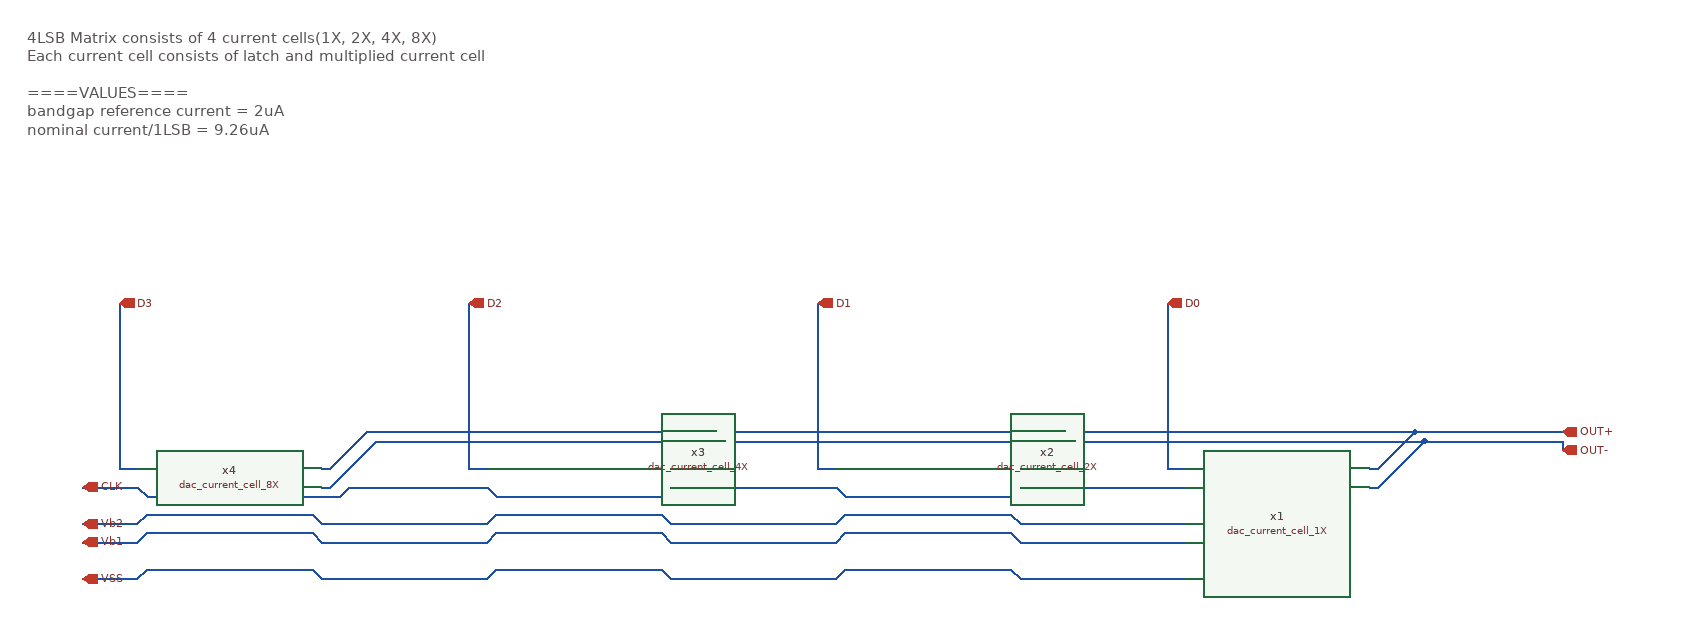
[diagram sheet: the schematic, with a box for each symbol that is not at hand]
v {xschem version=3.4.5 file_version=1.2
}
G {}
K {}
V {}
S {}
E {}
T {4LSB Matrix consists of 4 current cells(1X, 2X, 4X, 8X)
Each current cell consists of latch and multiplied current cell
 
====VALUES====
bandgap reference current = 2uA
nominal current/1LSB = 9.26uA} 20 -890 0 0 0.5 0.5 {}
N 900 -350 910 -360 {
lab=Vb2}
N 720 -290 890 -290 {
lab=VSS}
N 890 -290 900 -290 {
lab=VSS}
N 140 -290 150 -300 {
lab=VSS}
N 150 -300 320 -300 {
lab=VSS}
N 320 -300 330 -300 {
lab=VSS}
N 330 -300 340 -290 {
lab=VSS}
N 340 -290 520 -290 {
lab=VSS}
N 520 -290 530 -300 {
lab=VSS}
N 530 -300 710 -300 {
lab=VSS}
N 710 -300 720 -290 {
lab=VSS}
N 140 -350 150 -360 {
lab=Vb2}
N 150 -360 330 -360 {
lab=Vb2}
N 330 -360 340 -350 {
lab=Vb2}
N 340 -350 520 -350 {
lab=Vb2}
N 140 -330 150 -340 {
lab=Vb1}
N 150 -340 330 -340 {
lab=Vb1}
N 330 -340 340 -330 {
lab=Vb1}
N 340 -330 520 -330 {
lab=Vb1}
N 520 -350 530 -360 {
lab=Vb2}
N 530 -360 710 -360 {
lab=Vb2}
N 710 -360 720 -350 {
lab=Vb2}
N 720 -350 900 -350 {
lab=Vb2}
N 520 -330 530 -340 {
lab=Vb1}
N 530 -340 710 -340 {
lab=Vb1}
N 710 -340 720 -330 {
lab=Vb1}
N 720 -330 900 -330 {
lab=Vb1}
N 510 -390 520 -390 {
lab=CLK}
N 510 -410 520 -410 {
lab=D2}
N 910 -360 1090 -360 {
lab=Vb2}
N 1090 -360 1100 -350 {
lab=Vb2}
N 1100 -350 1280 -350 {
lab=Vb2}
N 900 -330 910 -340 {
lab=Vb1}
N 910 -340 1090 -340 {
lab=Vb1}
N 1090 -340 1100 -330 {
lab=Vb1}
N 1100 -330 1280 -330 {
lab=Vb1}
N 890 -410 900 -410 {
lab=D1}
N 1270 -410 1280 -410 {
lab=D0}
N 500 -590 500 -420 {
lab=D2}
N 500 -410 510 -410 {
lab=D2}
N 500 -420 500 -410 {
lab=D2}
N 120 -410 140 -410 {
lab=D3}
N 120 -590 120 -410 {
lab=D3}
N 880 -410 890 -410 {
lab=D1}
N 880 -590 880 -410 {
lab=D1}
N 1260 -410 1270 -410 {
lab=D0}
N 1260 -590 1260 -410 {
lab=D0}
N 890 -390 900 -390 {
lab=CLK}
N 1270 -390 1280 -390 {
lab=CLK}
N 700 -450 760 -450 {
lab=OUT+}
N 700 -440 770 -440 {
lab=OUT-}
N 760 -450 1140 -450 {
lab=OUT+}
N 770 -440 1150 -440 {
lab=OUT-}
N 1140 -450 1520 -450 {
lab=OUT+}
N 1150 -440 1530 -440 {
lab=OUT-}
N 900 -290 910 -300 {
lab=VSS}
N 910 -300 1090 -300 {
lab=VSS}
N 1090 -300 1100 -290 {
lab=VSS}
N 1100 -290 1280 -290 {
lab=VSS}
N 370 -390 510 -390 {
lab=CLK}
N 340 -390 350 -390 {
lab=OUT-}
N 340 -410 350 -410 {
lab=OUT+}
N 350 -410 390 -450 {
lab=OUT+}
N 720 -410 730 -410 {
lab=OUT+}
N 730 -410 770 -450 {
lab=OUT+}
N 720 -390 730 -390 {
lab=OUT-}
N 740 -390 890 -390 {
lab=CLK}
N 1100 -410 1110 -410 {
lab=OUT+}
N 1110 -410 1150 -450 {
lab=OUT+}
N 1100 -390 1110 -390 {
lab=OUT-}
N 1110 -390 1160 -440 {
lab=OUT-}
N 1120 -390 1270 -390 {
lab=CLK}
N 1480 -410 1490 -410 {
lab=OUT+}
N 1490 -410 1530 -450 {
lab=OUT+}
N 1480 -390 1490 -390 {
lab=OUT-}
N 1490 -390 1540 -440 {
lab=OUT-}
N 1530 -440 1540 -440 {
lab=OUT-}
N 1520 -450 1530 -450 {
lab=OUT+}
N 390 -450 700 -450 {
lab=OUT+}
N 400 -440 700 -440 {
lab=OUT-}
N 1530 -450 1690 -450 {
lab=OUT+}
N 1540 -440 1690 -440 {
lab=OUT-}
N 1690 -440 1690 -430 {
lab=OUT-}
N 350 -390 360 -400 {
lab=OUT-}
N 730 -390 740 -400 {
lab=OUT-}
N 140 -390 150 -380 {
lab=CLK}
N 150 -380 360 -380 {
lab=CLK}
N 360 -380 370 -390 {
lab=CLK}
N 520 -390 530 -380 {
lab=CLK}
N 530 -380 720 -380 {
lab=CLK}
N 360 -400 400 -440 {
lab=OUT-}
N 740 -400 780 -440 {
lab=OUT-}
N 720 -380 730 -380 {
lab=CLK}
N 730 -380 740 -390 {
lab=CLK}
N 900 -390 910 -380 {
lab=CLK}
N 910 -380 1110 -380 {
lab=CLK}
N 1110 -380 1120 -390 {
lab=CLK}
N 80 -390 140 -390 {
lab=CLK}
N 80 -350 140 -350 {
lab=Vb2}
N 80 -330 140 -330 {
lab=Vb1}
N 80 -290 140 -290 {
lab=VSS}
C {devices/ipin.sym} 80 -290 2 1 {name=p43 lab=VSS}
C {devices/opin.sym} 1690 -450 0 0 {name=p9 lab=OUT+}
C {devices/opin.sym} 1690 -430 0 0 {name=p10 lab=OUT-}
C {devices/ipin.sym} 80 -330 2 1 {name=p11 lab=Vb1}
C {devices/ipin.sym} 80 -350 2 1 {name=p13 lab=Vb2}
C {devices/ipin.sym} 80 -390 2 1 {name=p15 lab=CLK}
C {devices/ipin.sym} 120 -590 2 1 {name=p16 lab=D3}
C {devices/ipin.sym} 500 -590 2 1 {name=p17 lab=D2}
C {devices/ipin.sym} 880 -590 2 1 {name=p18 lab=D1}
C {devices/ipin.sym} 1260 -590 2 1 {name=p19 lab=D0}
C {dac_current_cell_8X.sym} 240 -350 0 0 {name=x4 DVDD=DVDD DVNW=DVNW DVPW=DVPW DVSS=DVSS}
C {dac_current_cell_4X.sym} 620 -350 0 0 {name=x3 DVDD=DVDD DVNW=DVNW DVPW=DVPW DVSS=DVSS}
C {dac_current_cell_2X.sym} 1000 -350 0 0 {name=x2 DVDD=DVDD DVNW=DVNW DVPW=DVPW DVSS=DVSS}
C {dac_current_cell_1X.sym} 1380 -350 0 0 {name=x1 DVDD=DVDD DVNW=DVNW DVPW=DVPW DVSS=DVSS}
C {devices/title.sym} 160 0 0 0 {name=l1 author="Junbeom Park"}
